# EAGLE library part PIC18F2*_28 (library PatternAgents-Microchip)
USB Microcontrollers with nanoWatt Technology High-Performance, Enhanced Flash, 28/40/44-Pin, Source: http://ww1.microchip.com/downloads/en/devicedoc/39632c.pdf

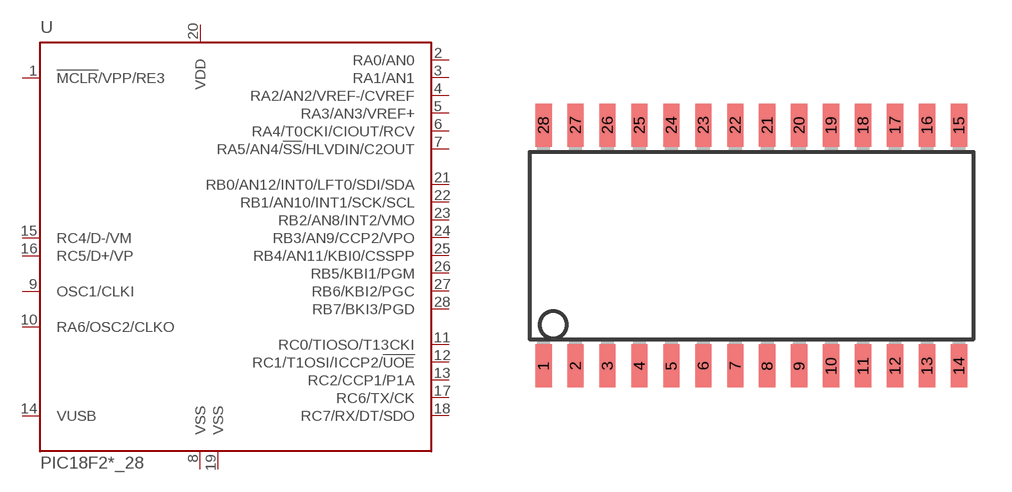
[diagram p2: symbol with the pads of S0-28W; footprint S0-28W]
Designator prefix -

## PIC18F2_28  [S0-28W]
1  !MCLR!/VPP/RE3  in
2  RA0/AN0
3  RA1/AN1
4  RA2/AN2/VREF-/CVREF
5  RA3/AN3/VREF+
6  RA4/T0CKI/CIOUT/RCV
7  RA5/AN4/!SS!/HLVDIN/C2OUT
8  VSS  pwr
9  OSC1/CLKI  in
10  RA6/OSC2/CLKO  out
11  RC0/TIOSO/T13CKI
12  RC1/T1OSI/ICCP2/!UOE
13  RC2/CCP1/P1A
14  VUSB
15  RC4/D-/VM
16  RC5/D+/VP
17  RC6/TX/CK
18  RC7/RX/DT/SDO
19  VSS  pwr
20  VDD  pwr
21  RB0/AN12/INT0/LFT0/SDI/SDA
22  RB1/AN10/INT1/SCK/SCL
23  RB2/AN8/INT2/VMO
24  RB3/AN9/CCP2/VPO
25  RB4/AN11/KBI0/CSSPP
26  RB5/KBI1/PGM
27  RB6/KBI2/PGC
28  RB7/BKI3/PGD

## Footprint S0-28W (pad centres in mm)
28-Lead Plastic Small Outline (SO) Wide, 300 mil Body (SOIC) Source: http://ww1.microchip.com/downloads/en/PackagingSpec/00049BF.pdf
smd 0.65 x 1.7: 1 -7.62,-4.78; 2 -6.35,-4.78; 3 -5.08,-4.78; 4 -3.81,-4.78; 5 -2.54,-4.78; 6 -1.27,-4.78; 7 0,-4.78; 8 1.27,-4.78; 9 2.54,-4.78; 10 3.81,-4.78; 11 5.08,-4.78; 12 6.35,-4.78; 13 7.62,-4.78; 14 8.89,-4.78; 15 8.89,4.78; 16 7.62,4.78; 17 6.35,4.78; 18 5.08,4.78; 19 3.81,4.78; 20 2.54,4.78; 21 1.27,4.78; 22 0,4.78; 23 -1.27,4.78; 24 -2.54,4.78; 25 -3.81,4.78; 26 -5.08,4.78; 27 -6.35,4.78; 28 -7.62,4.78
